VERSION 5.7 ;
  NOWIREEXTENSIONATPIN ON ;
  DIVIDERCHAR "/" ;
  BUSBITCHARS "[]" ;
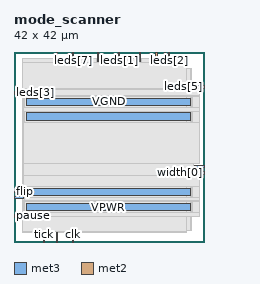
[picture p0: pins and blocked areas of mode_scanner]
MACRO mode_scanner
  CLASS BLOCK ;
  FOREIGN mode_scanner ;
  ORIGIN 0.000 0.000 ;
  SIZE 42.000 BY 42.000 ;
  PIN VGND
    DIRECTION INOUT ;
    USE GROUND ;
    PORT
      LAYER met3 ;
        RECT 2.760 10.220 39.100 11.820 ;
    END
    PORT
      LAYER met3 ;
        RECT 2.760 30.220 39.100 31.820 ;
    END
  END VGND
  PIN VPWR
    DIRECTION INOUT ;
    USE POWER ;
    PORT
      LAYER met3 ;
        RECT 2.760 6.920 39.100 8.520 ;
    END
    PORT
      LAYER met3 ;
        RECT 2.760 26.920 39.100 28.520 ;
    END
  END VPWR
  PIN clk
    DIRECTION INPUT ;
    USE SIGNAL ;
    ANTENNAGATEAREA 0.852000 ;
    PORT
      LAYER met2 ;
        RECT 12.970 0.000 13.250 2.000 ;
    END
  END clk
  PIN en
    DIRECTION INPUT ;
    USE SIGNAL ;
    ANTENNAGATEAREA 0.213000 ;
    PORT
      LAYER met2 ;
        RECT 9.290 0.000 9.570 2.000 ;
    END
  END en
  PIN flip
    DIRECTION INPUT ;
    USE SIGNAL ;
    ANTENNAGATEAREA 0.213000 ;
    PORT
      LAYER met3 ;
        RECT 0.000 10.920 2.000 11.520 ;
    END
  END flip
  PIN invert
    DIRECTION INPUT ;
    USE SIGNAL ;
    ANTENNAGATEAREA 0.495000 ;
    PORT
      LAYER met2 ;
        RECT 31.370 40.000 31.650 42.000 ;
    END
  END invert
  PIN leds[0]
    DIRECTION OUTPUT ;
    USE SIGNAL ;
    ANTENNADIFFAREA 0.795200 ;
    PORT
      LAYER met2 ;
        RECT 18.490 40.000 18.770 42.000 ;
    END
  END leds[0]
  PIN leds[1]
    DIRECTION OUTPUT ;
    USE SIGNAL ;
    ANTENNADIFFAREA 0.795200 ;
    PORT
      LAYER met2 ;
        RECT 23.090 40.000 23.370 42.000 ;
    END
  END leds[1]
  PIN leds[2]
    DIRECTION OUTPUT ;
    USE SIGNAL ;
    ANTENNADIFFAREA 0.795200 ;
    PORT
      LAYER met2 ;
        RECT 34.130 40.000 34.410 42.000 ;
    END
  END leds[2]
  PIN leds[3]
    DIRECTION OUTPUT ;
    USE SIGNAL ;
    ANTENNADIFFAREA 0.795200 ;
    PORT
      LAYER met3 ;
        RECT 0.000 32.680 2.000 33.280 ;
    END
  END leds[3]
  PIN leds[4]
    DIRECTION OUTPUT ;
    USE SIGNAL ;
    ANTENNADIFFAREA 0.795200 ;
    PORT
      LAYER met2 ;
        RECT 9.290 40.000 9.570 42.000 ;
    END
  END leds[4]
  PIN leds[5]
    DIRECTION OUTPUT ;
    USE SIGNAL ;
    ANTENNADIFFAREA 0.795200 ;
    PORT
      LAYER met3 ;
        RECT 40.000 34.040 42.000 34.640 ;
    END
  END leds[5]
  PIN leds[6]
    DIRECTION OUTPUT ;
    USE SIGNAL ;
    ANTENNADIFFAREA 0.795200 ;
    PORT
      LAYER met2 ;
        RECT 27.690 40.000 27.970 42.000 ;
    END
  END leds[6]
  PIN leds[7]
    DIRECTION OUTPUT ;
    USE SIGNAL ;
    ANTENNADIFFAREA 0.795200 ;
    PORT
      LAYER met2 ;
        RECT 12.970 40.000 13.250 42.000 ;
    END
  END leds[7]
  PIN pause
    DIRECTION INPUT ;
    USE SIGNAL ;
    ANTENNAGATEAREA 0.213000 ;
    PORT
      LAYER met3 ;
        RECT 0.000 5.480 2.000 6.080 ;
    END
  END pause
  PIN rst
    DIRECTION INPUT ;
    USE SIGNAL ;
    ANTENNAGATEAREA 0.213000 ;
    PORT
      LAYER met3 ;
        RECT 0.000 9.560 2.000 10.160 ;
    END
  END rst
  PIN split
    DIRECTION INPUT ;
    USE SIGNAL ;
    ANTENNAGATEAREA 0.213000 ;
    PORT
      LAYER met2 ;
        RECT 33.210 40.000 33.490 42.000 ;
    END
  END split
  PIN tick
    DIRECTION INPUT ;
    USE SIGNAL ;
    ANTENNAGATEAREA 0.213000 ;
    PORT
      LAYER met2 ;
        RECT 6.530 0.000 6.810 2.000 ;
    END
  END tick
  PIN width[0]
    DIRECTION INPUT ;
    USE SIGNAL ;
    ANTENNAGATEAREA 0.159000 ;
    PORT
      LAYER met3 ;
        RECT 40.000 15.000 42.000 15.600 ;
    END
  END width[0]
  PIN width[1]
    DIRECTION INPUT ;
    USE SIGNAL ;
    ANTENNAGATEAREA 0.159000 ;
    PORT
      LAYER met3 ;
        RECT 40.000 16.360 42.000 16.960 ;
    END
  END width[1]
  OBS
      LAYER nwell ;
        RECT 2.570 2.635 39.290 38.270 ;
      LAYER li1 ;
        RECT 2.760 2.635 39.100 38.165 ;
      LAYER met1 ;
        RECT 1.910 2.480 39.100 38.320 ;
      LAYER met2 ;
        RECT 1.930 39.720 9.010 40.530 ;
        RECT 9.850 39.720 12.690 40.530 ;
        RECT 13.530 39.720 18.210 40.530 ;
        RECT 19.050 39.720 22.810 40.530 ;
        RECT 23.650 39.720 27.410 40.530 ;
        RECT 28.250 39.720 31.090 40.530 ;
        RECT 31.930 39.720 32.930 40.530 ;
        RECT 33.770 39.720 33.850 40.530 ;
        RECT 34.690 39.720 38.090 40.530 ;
        RECT 1.930 2.280 38.090 39.720 ;
        RECT 1.930 2.000 6.250 2.280 ;
        RECT 7.090 2.000 9.010 2.280 ;
        RECT 9.850 2.000 12.690 2.280 ;
        RECT 13.530 2.000 38.090 2.280 ;
      LAYER met3 ;
        RECT 2.000 33.680 39.600 34.040 ;
        RECT 2.400 33.640 39.600 33.680 ;
        RECT 2.400 32.280 41.090 33.640 ;
        RECT 2.000 32.220 41.090 32.280 ;
        RECT 2.000 29.820 2.360 32.220 ;
        RECT 39.500 29.820 41.090 32.220 ;
        RECT 2.000 28.920 41.090 29.820 ;
        RECT 2.000 26.520 2.360 28.920 ;
        RECT 39.500 26.520 41.090 28.920 ;
        RECT 2.000 17.360 41.090 26.520 ;
        RECT 2.000 14.600 39.600 17.360 ;
        RECT 2.000 12.220 41.090 14.600 ;
        RECT 2.000 11.920 2.360 12.220 ;
        RECT 39.500 9.820 41.090 12.220 ;
        RECT 2.400 9.160 41.090 9.820 ;
        RECT 2.000 8.920 41.090 9.160 ;
        RECT 2.000 6.520 2.360 8.920 ;
        RECT 39.500 6.520 41.090 8.920 ;
        RECT 2.000 6.480 41.090 6.520 ;
        RECT 2.400 5.615 41.090 6.480 ;
  END
END mode_scanner
END LIBRARY

